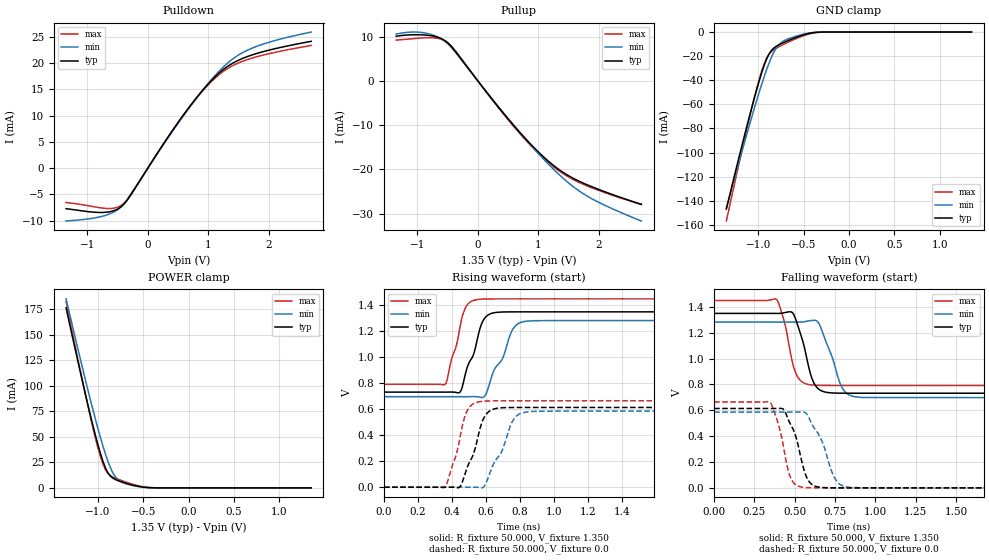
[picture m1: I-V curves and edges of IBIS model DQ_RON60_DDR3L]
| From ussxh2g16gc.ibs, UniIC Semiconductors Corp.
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|   Model DQ_RON60_DDR3L
[Model] DQ_RON60_DDR3L
Model_type I/O
Vinl =  0.540V
Vinh =  0.810V
Vmeas =  0.675V
Rref =  50.000
Vref =  0.675V
C_comp   0.966pF   0.965pF   0.967pF
[Model Spec]
Vinh   0.810V   0.776V   0.860V
Vinl   0.540V   0.506V   0.590V
Vmeas   0.675V   0.641V   0.725V
Vref   0.675V   0.641V   0.725V
Rref   50.000   NA   NA
[Temperature Range]   25.000   95.000   0.0
[Voltage Range]   1.350V   1.283V   1.450V
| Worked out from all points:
|   slope of the pulldown table from 0 to 0.203 V, typ, clamps not added: 55.8 ohm
|   slope of the pullup table from 0 to 0.203 V, typ, clamps not added: 56.9 ohm
|   GND clamp passes 1 mA (typ) near -0.43 V on its own axis
|   POWER clamp passes 1 mA (typ) near -0.52 V on its own axis
|   rising waveform, R_fixture 50.000, V_fixture 1.350: 20-80 % time 89.8ps typ, 116ps min, 75.1ps max; typ from 0.732 V to 1.35 V
|   rising waveform, R_fixture 50.000, V_fixture 0.0: 20-80 % time 92.1ps typ, 117ps min, 78.8ps max; typ from 0 V to 0.614 V
|   falling waveform, R_fixture 50.000, V_fixture 1.350: 20-80 % time 77.6ps typ, 96ps min, 68.5ps max; typ from 1.35 V to 0.732 V
|   falling waveform, R_fixture 50.000, V_fixture 0.0: 20-80 % time 87.8ps typ, 115ps min, 70.9ps max; typ from 0.614 V to 0 V
[Pulldown]
|Voltage   I(typ)   I(min)   I(max)
-1.35V    -7.722mA   -10.07mA   -6.542mA
-735mV    -8.434mA   -9.119mA   -7.633mA
-571mV    -8.147mA   -8.411mA   -7.646mA
-448mV    -7.434mA   -7.423mA   -7.166mA
-284mV    -5.144mA   -5.013mA   -5.147mA
290mV     5.156mA    5.047mA    5.173mA
659mV     11.23mA    11.12mA    11.2mA
946mV     15.38mA    15.42mA    15.23mA
1.192V    18.27mA    18.64mA    17.95mA
1.438V    20.22mA    21.1mA     19.74mA
1.725V    21.59mA    22.88mA    20.99mA
2.7V      24.18mA    25.94mA    23.39mA
[Pullup]
|Voltage   I(typ)   I(min)   I(max)
-1.35V    10.13mA    10.63mA    9.252mA
-1.072V   10.45mA    11.08mA    9.571mA
-867mV    10.39mA    10.84mA    9.791mA
-662mV    9.893mA    9.947mA    9.642mA
-498mV    8.614mA    8.428mA    8.67mA
-375mV    6.725mA    6.566mA    6.891mA
568mV     -9.667mA   -9.643mA   -9.902mA
896mV     -14.64mA   -14.85mA   -14.94mA
1.183V    -18.36mA   -19.06mA   -18.66mA
1.47V     -21.2mA    -22.74mA   -21.48mA
1.798V    -23.44mA   -25.97mA   -23.69mA
2.7V      -27.89mA   -31.66mA   -27.93mA
[GND_clamp]
|Voltage   I(typ)   I(min)   I(max)
-1.35V    -146.9mA   -146.3mA   -156.8mA
-1.154V   -87.06mA   -92.63mA   -90.37mA
-1.014V   -47.25mA   -56.31mA   -46.61mA
-958mV    -33.17mA   -42.77mA   -31.77mA
-930mV    -26.97mA   -36.36mA   -25.68mA
-902mV    -21.66mA   -30.3mA    -20.95mA
-846mV    -14.62mA   -19.69mA   -15.68mA
-790mV    -11.36mA   -12.14mA   -13.01mA
-734mV    -9.258mA   -8.096mA   -10.82mA
-566mV    -4.018mA   -3.098mA   -4.968mA
-398mV    -591.2uA   -439.3uA   -928.8uA
1.35V     0A         0A         0A
[POWER_clamp]
|Voltage   I(typ)   I(min)   I(max)
-1.35V    176.6mA    185.4mA    182.6mA
-1.226V   126.5mA    138.6mA    128.9mA
-1.114V   83.04mA    97.6mA     82.25mA
-1.03V    52.58mA    68.38mA    49.92mA
-974mV    34.42mA    50.13mA    31.33mA
-918mV    19.9mA     33.55mA    18.05mA
-890mV    14.85mA    26.22mA    14.28mA
-834mV    9.439mA    14.55mA    10.59mA
-778mV    7.089mA    7.901mA    8.471mA
-638mV    3.198mA    2.764mA    4.098mA
-414mV    126.6uA    165.9uA    198.4uA
1.35V     0A         0A         0A
[Ramp]
| variable   typ   min   max
dV/dt_r   0.369/92.016p   0.352/0.117n   0.399/78.794p
dV/dt_f   0.371/77.557p   0.351/96.063p   0.395/68.542p
R_load = 50.000
[Rising Waveform]
R_fixture= 50.000
V_fixture= 1.350
V_fixture_min= 1.283
V_fixture_max= 1.450
|time   V(typ)   V(min)   V(max)
0s        732.3mV    697.2mV    792.1mV
363ps     732.3mV    697.2mV    797.5mV
448ps     734.1mV    697.2mV    1.242V
485ps     905.3mV    697.2mV    1.396V
546ps     1.124V     696.8mV    1.444V
592ps     1.302V     702mV      1.449V
620ps     1.332V     797.4mV    1.45V
756ps     1.35V      1.215V     1.45V
834ps     1.35V      1.278V     1.45V
3ns       1.35V      1.283V     1.45V
[Rising Waveform]
R_fixture= 50.000
V_fixture= 0.0
V_fixture_min= 0.0
V_fixture_max= 0.0
|time   V(typ)   V(min)   V(max)
0s        169.2nV    1.221uV    191.4nV
355ps     -42uV      2.996uV    -2.291mV
449ps     8.193mV    -13.83uV   399.3mV
494ps     169.3mV    45.61uV    600.6mV
564ps     450.7mV    -3.339mV   659.1mV
630ps     594.1mV    136.9mV    664.6mV
691ps     611.6mV    273mV      665.2mV
751ps     613.9mV    498mV      665.3mV
811ps     614.2mV    573mV      665.3mV
3ns       614.2mV    586.3mV    665.3mV
[Falling Waveform]
R_fixture= 50.000
V_fixture= 1.350
V_fixture_min= 1.283
V_fixture_max= 1.450
|time   V(typ)   V(min)   V(max)
0s        1.35V      1.283V     1.45V
386ps     1.35V      1.283V     1.46V
440ps     1.357V     1.283V     1.265V
495ps     1.339V     1.283V     929.1mV
532ps     1.207V     1.283V     835.1mV
589ps     922.7mV    1.293V     799mV
664ps     751.7mV    1.234V     792.7mV
796ps     732.6mV    769.9mV    792.1mV
867ps     732.3mV    705.8mV    792.1mV
3ns       732.3mV    697.2mV    792.1mV
[Falling Waveform]
R_fixture= 50.000
V_fixture= 0.0
V_fixture_min= 0.0
V_fixture_max= 0.0
|time   V(typ)   V(min)   V(max)
0s        614.2mV    586.3mV    665.3mV
350ps     614.2mV    586.3mV    657.9mV
435ps     600.8mV    586.3mV    285.4mV
475ps     488.8mV    586.2mV    76.16mV
544ps     203.1mV    587.3mV    5.817mV
613ps     20.85mV    478.4mV    420.6uV
674ps     2.358mV    346.2mV    40.05uV
741ps     209.2uV    90.6mV     3.221uV
818ps     12.47uV    7.593mV    414.4nV
3ns       174.2nV    1.214uV    240.6nV
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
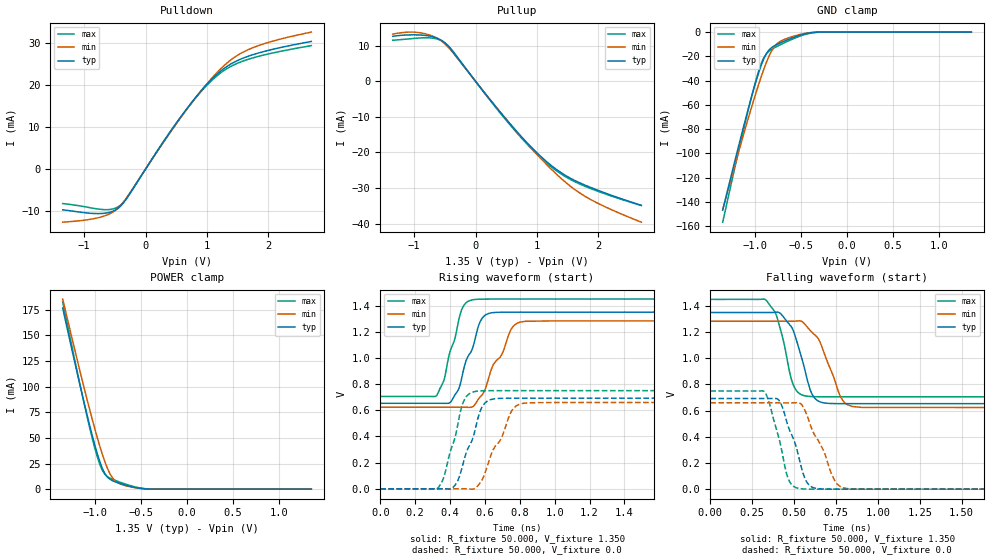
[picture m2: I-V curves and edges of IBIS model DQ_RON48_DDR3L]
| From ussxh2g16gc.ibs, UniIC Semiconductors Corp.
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|   Model DQ_RON48_DDR3L
[Model] DQ_RON48_DDR3L
Model_type I/O
Vinl =  0.540V
Vinh =  0.810V
Vmeas =  0.675V
Rref =  50.000
Vref =  0.675V
C_comp   0.966pF   0.965pF   0.967pF
[Model Spec]
Vinh   0.810V   0.776V   0.860V
Vinl   0.540V   0.506V   0.590V
Vmeas   0.675V   0.641V   0.725V
Vref   0.675V   0.641V   0.725V
Rref   50.000   NA   NA
[Temperature Range]   25.000   95.000   0.0
[Voltage Range]   1.350V   1.283V   1.450V
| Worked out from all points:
|   slope of the pulldown table from 0 to 0.203 V, typ, clamps not added: 44.6 ohm
|   slope of the pullup table from 0 to 0.203 V, typ, clamps not added: 45.5 ohm
|   GND clamp passes 1 mA (typ) near -0.43 V on its own axis
|   POWER clamp passes 1 mA (typ) near -0.52 V on its own axis
|   rising waveform, R_fixture 50.000, V_fixture 1.350: 20-80 % time 98.4ps typ, 130ps min, 81.8ps max; typ from 0.653 V to 1.35 V
|   rising waveform, R_fixture 50.000, V_fixture 0.0: 20-80 % time 99.3ps typ, 128ps min, 84.8ps max; typ from 0 V to 0.693 V
|   falling waveform, R_fixture 50.000, V_fixture 1.350: 20-80 % time 92.9ps typ, 118ps min, 79.8ps max; typ from 1.35 V to 0.653 V
|   falling waveform, R_fixture 50.000, V_fixture 0.0: 20-80 % time 102ps typ, 132ps min, 84.7ps max; typ from 0.693 V to 0 V
[Pulldown]
|Voltage   I(typ)   I(min)   I(max)
-1.35V    -9.661mA   -12.6mA    -8.186mA
-735mV    -10.55mA   -11.4mA    -9.549mA
-571mV    -10.19mA   -10.52mA   -9.563mA
-448mV    -9.296mA   -9.283mA   -8.961mA
-284mV    -6.433mA   -6.269mA   -6.436mA
290mV     6.447mA    6.311mA    6.469mA
659mV     14.05mA    13.9mA     14mA
946mV     19.24mA    19.29mA    19.05mA
1.192V    22.85mA    23.31mA    22.46mA
1.438V    25.3mA     26.4mA     24.7mA
1.725V    27.01mA    28.63mA    26.26mA
2.7V      30.25mA    32.47mA    29.27mA
[Pullup]
|Voltage   I(typ)   I(min)   I(max)
-1.35V    12.67mA    13.29mA    11.57mA
-1.072V   13.07mA    13.86mA    11.97mA
-867mV    13mA       13.56mA    12.24mA
-662mV    12.37mA    12.44mA    12.05mA
-498mV    10.77mA    10.54mA    10.84mA
-375mV    8.408mA    8.211mA    8.615mA
568mV     -12.09mA   -12.06mA   -12.38mA
896mV     -18.3mA    -18.57mA   -18.67mA
1.183V    -22.95mA   -23.83mA   -23.33mA
1.47V     -26.5mA    -28.44mA   -26.85mA
1.798V    -29.29mA   -32.48mA   -29.61mA
2.7V      -34.86mA   -39.6mA    -34.91mA
[GND_clamp]
|Voltage   I(typ)   I(min)   I(max)
-1.35V    -146.9mA   -146.3mA   -156.8mA
-1.154V   -87.06mA   -92.63mA   -90.37mA
-1.014V   -47.25mA   -56.31mA   -46.61mA
-958mV    -33.17mA   -42.77mA   -31.77mA
-930mV    -26.97mA   -36.36mA   -25.68mA
-902mV    -21.66mA   -30.3mA    -20.95mA
-846mV    -14.62mA   -19.69mA   -15.68mA
-790mV    -11.36mA   -12.14mA   -13.01mA
-734mV    -9.258mA   -8.096mA   -10.82mA
-566mV    -4.018mA   -3.098mA   -4.968mA
-398mV    -591.2uA   -439.3uA   -928.8uA
1.35V     0A         0A         0A
[POWER_clamp]
|Voltage   I(typ)   I(min)   I(max)
-1.35V    176.6mA    185.4mA    182.6mA
-1.226V   126.5mA    138.6mA    128.9mA
-1.114V   83.04mA    97.6mA     82.25mA
-1.03V    52.58mA    68.38mA    49.92mA
-974mV    34.42mA    50.13mA    31.33mA
-918mV    19.9mA     33.55mA    18.05mA
-890mV    14.85mA    26.22mA    14.28mA
-834mV    9.439mA    14.55mA    10.59mA
-778mV    7.089mA    7.901mA    8.471mA
-638mV    3.198mA    2.764mA    4.098mA
-414mV    126.6uA    165.9uA    198.4uA
1.35V     0A         0A         0A
[Ramp]
| variable   typ   min   max
dV/dt_r   0.416/99.045p   0.396/0.128n   0.450/84.592p
dV/dt_f   0.418/92.332p   0.396/0.118n   0.447/79.829p
R_load = 50.000
[Rising Waveform]
R_fixture= 50.000
V_fixture= 1.350
V_fixture_min= 1.283
V_fixture_max= 1.450
|time   V(typ)   V(min)   V(max)
0s        653.2mV    623.3mV    705.7mV
324ps     653.2mV    623.3mV    715mV
364ps     653mV      623.3mV    825.5mV
408ps     671.1mV    623.3mV    1.079V
474ps     889.9mV    623.3mV    1.39V
533ps     1.09V      630mV      1.445V
598ps     1.323V     749.6mV    1.45V
751ps     1.35V      1.221V     1.45V
801ps     1.35V      1.274V     1.45V
3ns       1.35V      1.283V     1.45V
[Rising Waveform]
R_fixture= 50.000
V_fixture= 0.0
V_fixture_min= 0.0
V_fixture_max= 0.0
|time   V(typ)   V(min)   V(max)
0s        157.3nV    1.097uV    182.3nV
332ps     8.979uV    4.384uV    7.453mV
365ps     90.37uV    3.574uV    91.58mV
440ps     50.59mV    18.29uV    459.3mV
485ps     241.9mV    160.2uV    687.4mV
549ps     479.5mV    8.874mV    744.8mV
611ps     667.7mV    162.1mV    749.8mV
754ps     692.5mV    596.5mV    750.3mV
816ps     692.6mV    652.5mV    750.3mV
3ns       692.6mV    659.5mV    750.3mV
[Falling Waveform]
R_fixture= 50.000
V_fixture= 1.350
V_fixture_min= 1.283
V_fixture_max= 1.450
|time   V(typ)   V(min)   V(max)
0s        1.35V      1.283V     1.45V
333ps     1.35V      1.283V     1.444V
400ps     1.353V     1.283V     1.306V
484ps     1.24V      1.283V     839.5mV
563ps     919.9mV    1.263V     713.7mV
597ps     756.1mV    1.212V     708.1mV
641ps     675.8mV    1.157V     706.2mV
778ps     653.3mV    704.1mV    705.7mV
847ps     653.2mV    631.6mV    705.7mV
3ns       653.2mV    623.3mV    705.7mV
[Falling Waveform]
R_fixture= 50.000
V_fixture= 0.0
V_fixture_min= 0.0
V_fixture_max= 0.0
|time   V(typ)   V(min)   V(max)
0s        692.6mV    659.5mV    750.3mV
321ps     692.5mV    659.5mV    747.7mV
413ps     673.3mV    659.5mV    372.6mV
463ps     486.6mV    659.4mV    86.98mV
528ps     247.4mV    659.5mV    5.817mV
563ps     87.33mV    607mV      1.318mV
601ps     20.4mV     476.8mV    260.2uV
745ps     64.03uV    58.83mV    752.8nV
812ps     4.268uV    5.401mV    289.2nV
3ns       139.7nV    1.088uV    228.8nV
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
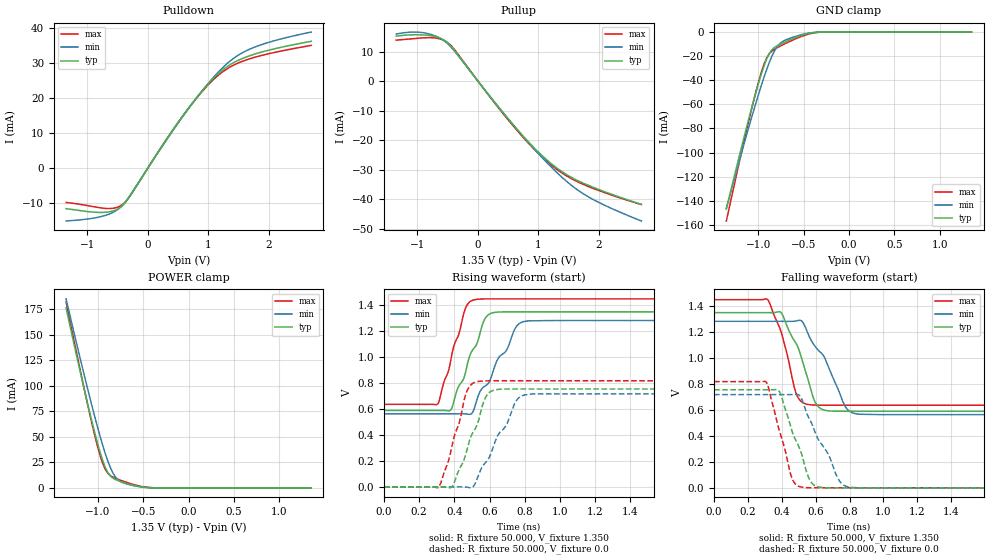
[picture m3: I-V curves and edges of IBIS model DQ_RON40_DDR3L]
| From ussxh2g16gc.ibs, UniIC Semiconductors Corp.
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|   Model DQ_RON40_DDR3L
[Model] DQ_RON40_DDR3L
Model_type I/O
Vinl =  0.540V
Vinh =  0.810V
Vmeas =  0.675V
Rref =  50.000
Vref =  0.675V
C_comp   0.966pF   0.965pF   0.967pF
[Model Spec]
Vinh   0.810V   0.776V   0.860V
Vinl   0.540V   0.506V   0.590V
Vmeas   0.675V   0.641V   0.725V
Vref   0.675V   0.641V   0.725V
Rref   50.000   NA   NA
[Temperature Range]   25.000   95.000   0.0
[Voltage Range]   1.350V   1.283V   1.450V
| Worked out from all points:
|   slope of the pulldown table from 0 to 0.203 V, typ, clamps not added: 37.2 ohm
|   slope of the pullup table from 0 to 0.203 V, typ, clamps not added: 38 ohm
|   GND clamp passes 1 mA (typ) near -0.43 V on its own axis
|   POWER clamp passes 1 mA (typ) near -0.52 V on its own axis
|   rising waveform, R_fixture 50.000, V_fixture 1.350: 20-80 % time 134ps typ, 184ps min, 106ps max; typ from 0.59 V to 1.35 V
|   rising waveform, R_fixture 50.000, V_fixture 0.0: 20-80 % time 122ps typ, 170ps min, 96.3ps max; typ from 0 V to 0.756 V
|   falling waveform, R_fixture 50.000, V_fixture 1.350: 20-80 % time 128ps typ, 175ps min, 101ps max; typ from 1.35 V to 0.59 V
|   falling waveform, R_fixture 50.000, V_fixture 0.0: 20-80 % time 119ps typ, 161ps min, 97.6ps max; typ from 0.756 V to 0 V
[Pulldown]
|Voltage   I(typ)   I(min)   I(max)
-1.35V    -11.58mA   -15.1mA    -9.807mA
-735mV    -12.64mA   -13.67mA   -11.44mA
-571mV    -12.21mA   -12.61mA   -11.46mA
-448mV    -11.14mA   -11.13mA   -10.74mA
-284mV    -7.708mA   -7.512mA   -7.711mA
290mV     7.725mA    7.562mA    7.75mA
659mV     16.83mA    16.66mA    16.78mA
946mV     23.05mA    23.11mA    22.82mA
1.192V    27.38mA    27.92mA    26.9mA
1.438V    30.3mA     31.62mA    29.59mA
1.725V    32.35mA    34.28mA    31.45mA
2.7V      36.23mA    38.87mA    35.06mA
[Pullup]
|Voltage   I(typ)   I(min)   I(max)
-1.35V    15.19mA    15.93mA    13.87mA
-1.072V   15.67mA    16.61mA    14.35mA
-867mV    15.58mA    16.25mA    14.68mA
-662mV    14.83mA    14.91mA    14.45mA
-498mV    12.91mA    12.63mA    12.99mA
-375mV    10.07mA    9.838mA    10.32mA
568mV     -14.48mA   -14.45mA   -14.83mA
896mV     -21.93mA   -22.25mA   -22.38mA
1.183V    -27.5mA    -28.54mA   -27.96mA
1.47V     -31.76mA   -34.06mA   -32.18mA
1.798V    -35.1mA    -38.89mA   -35.48mA
2.7V      -41.76mA   -47.4mA    -41.83mA
[GND_clamp]
|Voltage   I(typ)   I(min)   I(max)
-1.35V    -146.9mA   -146.3mA   -156.8mA
-1.154V   -87.06mA   -92.63mA   -90.37mA
-1.014V   -47.25mA   -56.31mA   -46.61mA
-958mV    -33.17mA   -42.77mA   -31.77mA
-930mV    -26.97mA   -36.36mA   -25.68mA
-902mV    -21.66mA   -30.3mA    -20.95mA
-846mV    -14.62mA   -19.69mA   -15.68mA
-790mV    -11.36mA   -12.14mA   -13.01mA
-734mV    -9.258mA   -8.096mA   -10.82mA
-566mV    -4.018mA   -3.098mA   -4.968mA
-398mV    -591.2uA   -439.3uA   -928.8uA
1.35V     0A         0A         0A
[POWER_clamp]
|Voltage   I(typ)   I(min)   I(max)
-1.35V    176.6mA    185.4mA    182.6mA
-1.226V   126.5mA    138.6mA    128.9mA
-1.114V   83.04mA    97.6mA     82.25mA
-1.03V    52.58mA    68.38mA    49.92mA
-974mV    34.42mA    50.13mA    31.33mA
-918mV    19.9mA     33.55mA    18.05mA
-890mV    14.85mA    26.22mA    14.28mA
-834mV    9.439mA    14.55mA    10.59mA
-778mV    7.089mA    7.901mA    8.471mA
-638mV    3.198mA    2.764mA    4.098mA
-414mV    126.6uA    165.9uA    198.4uA
1.35V     0A         0A         0A
[Ramp]
| variable   typ   min   max
dV/dt_r   0.453/0.121n   0.431/0.169n   0.491/96.165p
dV/dt_f   0.456/0.128n   0.431/0.176n   0.488/0.100n
R_load = 50.000
[Rising Waveform]
R_fixture= 50.000
V_fixture= 1.350
V_fixture_min= 1.283
V_fixture_max= 1.450
|time   V(typ)   V(min)   V(max)
0s        589.8mV    563.9mV    636.7mV
307ps     589.8mV    563.9mV    641.3mV
382ps     598.9mV    563.8mV    994.6mV
464ps     886.5mV    563.1mV    1.38V
497ps     1.041V     564.3mV    1.435V
522ps     1.088V     644.1mV    1.445V
592ps     1.326V     796.5mV    1.45V
745ps     1.35V      1.221V     1.45V
797ps     1.35V      1.276V     1.45V
3ns       1.35V      1.283V     1.45V
[Rising Waveform]
R_fixture= 50.000
V_fixture= 0.0
V_fixture_min= 0.0
V_fixture_max= 0.0
|time   V(typ)   V(min)   V(max)
0s        148nV      998nV      175.6nV
314ps     21.36uV    2.887uV    4.402mV
390ps     7.276mV    -48.9uV    337mV
469ps     271.7mV    -1.084mV   731.2mV
535ps     501.8mV    82.53mV    812.9mV
570ps     670.1mV    177.3mV    817.2mV
603ps     732.5mV    242.9mV    818.1mV
752ps     755.6mV    665.2mV    818.5mV
795ps     755.6mV    708.3mV    818.5mV
3ns       755.6mV    718.3mV    818.5mV
[Falling Waveform]
R_fixture= 50.000
V_fixture= 1.350
V_fixture_min= 1.283
V_fixture_max= 1.450
|time   V(typ)   V(min)   V(max)
0s        1.35V      1.283V     1.45V
315ps     1.35V      1.283V     1.452V
401ps     1.341V     1.283V     1.178V
481ps     1.119V     1.285V     741.1mV
519ps     989.3mV    1.284V     660.6mV
552ps     846.7mV    1.196V     643mV
625ps     614mV      1.048V     637mV
773ps     589.9mV    628.9mV    636.7mV
835ps     589.8mV    571mV      636.7mV
3ns       589.8mV    563.9mV    636.7mV
[Falling Waveform]
R_fixture= 50.000
V_fixture= 0.0
V_fixture_min= 0.0
V_fixture_max= 0.0
|time   V(typ)   V(min)   V(max)
0s        755.6mV    718.3mV    818.5mV
305ps     755.5mV    718.3mV    818mV
387ps     739.4mV    718.3mV    434mV
462ps     429.8mV    718.4mV    67.54mV
512ps     279.2mV    698.9mV    6.791mV
551ps     103.6mV    562.4mV    1.097mV
588ps     23.25mV    457.8mV    194.8uV
741ps     30.01uV    50.75mV    406.8nV
787ps     4.187uV    8.759mV    248.8nV
3ns       95.89nV    981nV      156.4nV
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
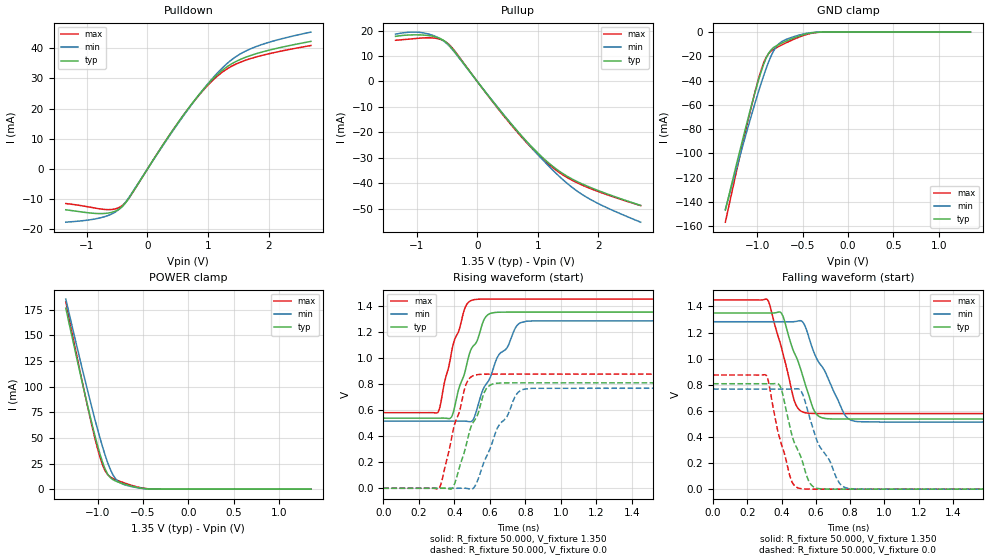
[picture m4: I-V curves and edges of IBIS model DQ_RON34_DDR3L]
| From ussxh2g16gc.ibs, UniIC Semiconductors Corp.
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|   Model DQ_RON34_DDR3L
[Model] DQ_RON34_DDR3L
Model_type I/O
Vinl =  0.540V
Vinh =  0.810V
Vmeas =  0.675V
Rref =  50.000
Vref =  0.675V
C_comp   0.966pF   0.965pF   0.967pF
[Model Spec]
Vinh   0.810V   0.776V   0.860V
Vinl   0.540V   0.506V   0.590V
Vmeas   0.675V   0.641V   0.725V
Vref   0.675V   0.641V   0.725V
Rref   50.000   NA   NA
[Temperature Range]   25.000   95.000   0.0
[Voltage Range]   1.350V   1.283V   1.450V
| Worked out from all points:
|   slope of the pulldown table from 0 to 0.203 V, typ, clamps not added: 31.9 ohm
|   slope of the pullup table from 0 to 0.203 V, typ, clamps not added: 32.6 ohm
|   GND clamp passes 1 mA (typ) near -0.43 V on its own axis
|   POWER clamp passes 1 mA (typ) near -0.52 V on its own axis
|   rising waveform, R_fixture 50.000, V_fixture 1.350: 20-80 % time 128ps typ, 174ps min, 102ps max; typ from 0.537 V to 1.35 V
|   rising waveform, R_fixture 50.000, V_fixture 0.0: 20-80 % time 120ps typ, 161ps min, 97.7ps max; typ from 0 V to 0.808 V
|   falling waveform, R_fixture 50.000, V_fixture 1.350: 20-80 % time 125ps typ, 167ps min, 103ps max; typ from 1.35 V to 0.537 V
|   falling waveform, R_fixture 50.000, V_fixture 0.0: 20-80 % time 113ps typ, 150ps min, 94ps max; typ from 0.808 V to 0 V
[Pulldown]
|Voltage   I(typ)   I(min)   I(max)
-1.35V    -13.51mA   -17.62mA   -11.45mA
-735mV    -14.75mA   -15.95mA   -13.35mA
-571mV    -14.25mA   -14.71mA   -13.37mA
-448mV    -12.99mA   -12.97mA   -12.53mA
-284mV    -8.986mA   -8.758mA   -8.991mA
290mV     9.006mA    8.816mA    9.037mA
659mV     19.63mA    19.42mA    19.56mA
946mV     26.88mA    26.94mA    26.61mA
1.192V    31.92mA    32.56mA    31.37mA
1.438V    35.34mA    36.87mA    34.5mA
1.725V    37.72mA    39.98mA    36.68mA
2.7V      42.25mA    45.33mA    40.89mA
[Pullup]
|Voltage   I(typ)   I(min)   I(max)
-1.35V    17.72mA    18.59mA    16.18mA
-1.072V   18.28mA    19.38mA    16.74mA
-867mV    18.18mA    18.96mA    17.12mA
-662mV    17.3mA     17.39mA    16.86mA
-498mV    15.05mA    14.73mA    15.15mA
-375mV    11.75mA    11.47mA    12.04mA
568mV     -16.88mA   -16.85mA   -17.3mA
896mV     -25.56mA   -25.94mA   -26.09mA
1.183V    -32.06mA   -33.29mA   -32.6mA
1.47V     -37.02mA   -39.71mA   -37.52mA
1.798V    -40.91mA   -45.34mA   -41.37mA
2.7V      -48.67mA   -55.27mA   -48.76mA
[GND_clamp]
|Voltage   I(typ)   I(min)   I(max)
-1.35V    -146.9mA   -146.3mA   -156.8mA
-1.154V   -87.06mA   -92.63mA   -90.37mA
-1.014V   -47.25mA   -56.31mA   -46.61mA
-958mV    -33.17mA   -42.77mA   -31.77mA
-930mV    -26.97mA   -36.36mA   -25.68mA
-902mV    -21.66mA   -30.3mA    -20.95mA
-846mV    -14.62mA   -19.69mA   -15.68mA
-790mV    -11.36mA   -12.14mA   -13.01mA
-734mV    -9.258mA   -8.096mA   -10.82mA
-566mV    -4.018mA   -3.098mA   -4.968mA
-398mV    -591.2uA   -439.3uA   -928.8uA
1.35V     0A         0A         0A
[POWER_clamp]
|Voltage   I(typ)   I(min)   I(max)
-1.35V    176.6mA    185.4mA    182.6mA
-1.226V   126.5mA    138.6mA    128.9mA
-1.114V   83.04mA    97.6mA     82.25mA
-1.03V    52.58mA    68.38mA    49.92mA
-974mV    34.42mA    50.13mA    31.33mA
-918mV    19.9mA     33.55mA    18.05mA
-890mV    14.85mA    26.22mA    14.28mA
-834mV    9.439mA    14.55mA    10.59mA
-778mV    7.089mA    7.901mA    8.471mA
-638mV    3.198mA    2.764mA    4.098mA
-414mV    126.6uA    165.9uA    198.4uA
1.35V     0A         0A         0A
[Ramp]
| variable   typ   min   max
dV/dt_r   0.485/0.120n   0.460/0.161n   0.525/97.835p
dV/dt_f   0.488/0.125n   0.461/0.167n   0.522/0.103n
R_load = 50.000
[Rising Waveform]
R_fixture= 50.000
V_fixture= 1.350
V_fixture_min= 1.283
V_fixture_max= 1.450
|time   V(typ)   V(min)   V(max)
0s        537.3mV    514.5mV    579.5mV
307ps     537.3mV    514.5mV    580.4mV
384ps     545.9mV    514.5mV    1.043V
459ps     887.4mV    514.5mV    1.379V
507ps     1.091V     528mV      1.444V
593ps     1.334V     824.6mV    1.45V
639ps     1.348V     995.1mV    1.45V
745ps     1.35V      1.232V     1.45V
806ps     1.35V      1.28V      1.45V
3ns       1.35V      1.283V     1.45V
[Rising Waveform]
R_fixture= 50.000
V_fixture= 0.0
V_fixture_min= 0.0
V_fixture_max= 0.0
|time   V(typ)   V(min)   V(max)
0s        140.3nV    915.5nV    169.7nV
313ps     -21.49uV   3.362uV    -927.8uV
395ps     15.21mV    -61.63uV   456.5mV
467ps     333mV      -390.9uV   800.3mV
516ps     524.4mV    16.05mV    867mV
569ps     735.9mV    207.5mV    874.2mV
600ps     789.3mV    299.8mV    874.7mV
641ps     804.9mV    459.5mV    874.9mV
789ps     807.9mV    758.4mV    874.9mV
3ns       807.9mV    767.3mV    874.9mV
[Falling Waveform]
R_fixture= 50.000
V_fixture= 1.350
V_fixture_min= 1.283
V_fixture_max= 1.450
|time   V(typ)   V(min)   V(max)
0s        1.35V      1.283V     1.45V
316ps     1.35V      1.283V     1.453V
400ps     1.347V     1.283V     1.079V
476ps     1.039V     1.284V     670.6mV
535ps     816mV      1.255V     586.6mV
584ps     618.5mV    1.064V     580.3mV
613ps     562.1mV    980.2mV    579.7mV
764ps     537.4mV    579.1mV    579.5mV
827ps     537.3mV    520.4mV    579.5mV
3ns       537.3mV    514.5mV    579.5mV
[Falling Waveform]
R_fixture= 50.000
V_fixture= 0.0
V_fixture_min= 0.0
V_fixture_max= 0.0
|time   V(typ)   V(min)   V(max)
0s        807.9mV    767.3mV    874.9mV
311ps     807.8mV    767.3mV    871.1mV
395ps     777.9mV    767.3mV    361.5mV
456ps     435.6mV    767.1mV    69.66mV
505ps     269.7mV    764.4mV    6.098mV
555ps     71.88mV    587.9mV    490.7uV
584ps     19.73mV    462.8mV    115.2uV
722ps     36.48uV    81.4mV     400nV
783ps     2.599uV    7.159mV    255.7nV
3ns       78.32nV    867.5nV    176.3nV
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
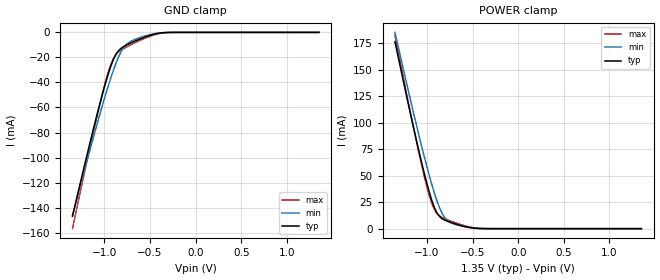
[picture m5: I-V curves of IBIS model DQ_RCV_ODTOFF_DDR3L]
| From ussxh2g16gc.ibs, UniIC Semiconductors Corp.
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|   Model DQ_RCV_ODTOFF_DDR3L
[Model] DQ_RCV_ODTOFF_DDR3L
Model_type Input
Vinl =  0.540V
Vinh =  0.810V
C_comp   0.966pF   0.965pF   0.967pF
[Model Spec]
Vinh   0.810V   0.776V   0.860V
Vinl   0.540V   0.506V   0.590V
[Temperature Range]   25.000   95.000   0.0
[Voltage Range]   1.350V   1.283V   1.450V
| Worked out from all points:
|   GND clamp passes 1 mA (typ) near -0.43 V on its own axis
|   POWER clamp passes 1 mA (typ) near -0.52 V on its own axis
[GND_clamp]
|Voltage   I(typ)   I(min)   I(max)
-1.35V    -146.9mA   -146.3mA   -156.8mA
-1.154V   -87.06mA   -92.63mA   -90.37mA
-1.014V   -47.25mA   -56.31mA   -46.61mA
-958mV    -33.17mA   -42.77mA   -31.77mA
-930mV    -26.97mA   -36.36mA   -25.68mA
-902mV    -21.66mA   -30.3mA    -20.95mA
-846mV    -14.62mA   -19.69mA   -15.68mA
-790mV    -11.36mA   -12.14mA   -13.01mA
-734mV    -9.258mA   -8.096mA   -10.82mA
-566mV    -4.018mA   -3.098mA   -4.968mA
-398mV    -591.2uA   -439.3uA   -928.8uA
1.35V     0A         0A         0A
[POWER_clamp]
|Voltage   I(typ)   I(min)   I(max)
-1.35V    176.6mA    185.4mA    182.6mA
-1.226V   126.5mA    138.6mA    128.9mA
-1.114V   83.04mA    97.6mA     82.25mA
-1.03V    52.58mA    68.38mA    49.92mA
-974mV    34.42mA    50.13mA    31.33mA
-918mV    19.9mA     33.55mA    18.05mA
-890mV    14.85mA    26.22mA    14.28mA
-834mV    9.439mA    14.55mA    10.59mA
-778mV    7.089mA    7.901mA    8.471mA
-638mV    3.198mA    2.764mA    4.098mA
-414mV    126.6uA    165.9uA    198.4uA
1.35V     0A         0A         0A
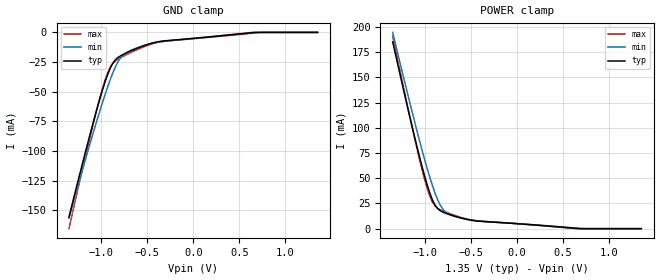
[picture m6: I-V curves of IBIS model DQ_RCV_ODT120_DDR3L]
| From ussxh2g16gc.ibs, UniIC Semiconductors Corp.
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|   Model DQ_RCV_ODT120_DDR3L
[Model] DQ_RCV_ODT120_DDR3L
Model_type Input
Vinl =  0.540V
Vinh =  0.810V
C_comp   0.966pF   0.965pF   0.967pF
[Model Spec]
Vinh   0.810V   0.776V   0.860V
Vinl   0.540V   0.506V   0.590V
[Temperature Range]   25.000   95.000   0.0
[Voltage Range]   1.350V   1.283V   1.450V
[GND_clamp]
|Voltage   I(typ)   I(min)   I(max)
-1.35V    -155.9mA   -156.8mA   -165.6mA
-1.154V   -95.85mA   -102.7mA   -98.99mA
-1.014V   -55.93mA   -66.14mA   -55.14mA
-930mV    -35.58mA   -46.03mA   -34.17mA
-902mV    -30.24mA   -39.91mA   -29.42mA
-846mV    -23.14mA   -29.18mA   -24.11mA
-790mV    -19.82mA   -21.51mA   -21.41mA
-734mV    -17.64mA   -17.32mA   -19.17mA
-594mV    -12.95mA   -12.57mA   -14.05mA
-398mV    -8.128mA   -8.424mA   -8.63mA
638mV     -251.5uA   -28.29uA   -706.4uA
1.35V     0A         0A         0A
[POWER_clamp]
|Voltage   I(typ)   I(min)   I(max)
-1.35V    185.2mA    194.6mA    190.9mA
-1.114V   91.62mA    106.7mA    90.46mA
-1.03V    61.11mA    77.45mA    58.1mA
-974mV    42.92mA    59.15mA    39.5mA
-918mV    28.35mA    42.51mA    26.21mA
-890mV    23.28mA    35.15mA    22.43mA
-834mV    17.82mA    23.39mA    18.72mA
-778mV    15.41mA    16.65mA    16.56mA
-638mV    11.3mA     11.2mA     12.04mA
-386mV    7.244mA    7.486mA    7.248mA
650mV     229.5uA    0A         519.8uA
1.35V     0A         0A         0A
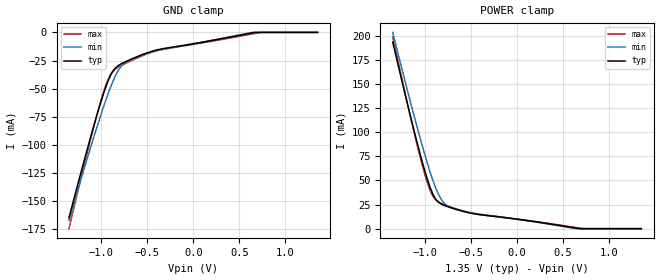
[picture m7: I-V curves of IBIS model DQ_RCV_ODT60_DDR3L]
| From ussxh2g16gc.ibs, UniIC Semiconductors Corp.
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|   Model DQ_RCV_ODT60_DDR3L
[Model] DQ_RCV_ODT60_DDR3L
Model_type Input
Vinl =  0.540V
Vinh =  0.810V
C_comp   0.966pF   0.965pF   0.967pF
[Model Spec]
Vinh   0.810V   0.776V   0.860V
Vinl   0.540V   0.506V   0.590V
[Temperature Range]   25.000   95.000   0.0
[Voltage Range]   1.350V   1.283V   1.450V
[GND_clamp]
|Voltage   I(typ)   I(min)   I(max)
-1.35V    -164.8mA   -167.1mA   -174.3mA
-1.154V   -104.6mA   -112.7mA   -107.6mA
-1.014V   -64.57mA   -75.87mA   -63.63mA
-930mV    -44.15mA   -55.6mA    -42.61mA
-902mV    -38.78mA   -49.43mA   -37.85mA
-846mV    -31.62mA   -38.58mA   -32.51mA
-790mV    -28.24mA   -30.79mA   -29.77mA
-734mV    -25.99mA   -26.47mA   -27.48mA
-370mV    -15.11mA   -15.83mA   -15.71mA
638mV     -505uA     -51.4uA    -1.415mA
750mV     0A         0A         0A
1.35V     0A         0A         0A
[POWER_clamp]
|Voltage   I(typ)   I(min)   I(max)
-1.35V    193.8mA    203.7mA    199.1mA
-1.114V   100.1mA    115.8mA    98.59mA
-1.03V    69.57mA    86.43mA    66.22mA
-974mV    51.35mA    68.08mA    47.61mA
-918mV    36.74mA    51.37mA    34.3mA
-890mV    31.65mA    43.97mA    30.51mA
-834mV    26.13mA    32.14mA    26.77mA
-778mV    23.66mA    25.3mA     24.58mA
-666mV    20.13mA    20.3mA     20.8mA
-442mV    15.1mA     15.57mA    15.13mA
622mV     886.5uA    316.9uA    1.45mA
1.35V     0A         0A         0A
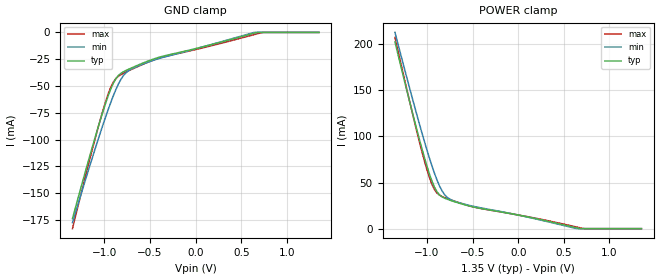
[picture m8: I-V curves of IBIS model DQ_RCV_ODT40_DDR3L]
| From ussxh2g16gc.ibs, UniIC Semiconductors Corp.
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|   Model DQ_RCV_ODT40_DDR3L
[Model] DQ_RCV_ODT40_DDR3L
Model_type Input
Vinl =  0.540V
Vinh =  0.810V
C_comp   0.966pF   0.965pF   0.967pF
[Model Spec]
Vinh   0.810V   0.776V   0.860V
Vinl   0.540V   0.506V   0.590V
[Temperature Range]   25.000   95.000   0.0
[Voltage Range]   1.350V   1.283V   1.450V
[GND_clamp]
|Voltage   I(typ)   I(min)   I(max)
-1.35V    -173.6mA   -177.4mA   -183mA
-1.154V   -113.3mA   -122.7mA   -116.1mA
-1.014V   -73.19mA   -85.62mA   -72.12mA
-930mV    -52.69mA   -65.19mA   -51.05mA
-902mV    -47.3mA    -58.96mA   -46.27mA
-846mV    -40.08mA   -48mA      -40.89mA
-762mV    -35.42mA   -37.49mA   -36.93mA
-566mV    -28.17mA   -29.17mA   -29.32mA
-342mV    -21.84mA   -22.94mA   -22.59mA
638mV     -757.9uA   -84.43uA   -2.121mA
750mV     0A         0A         0A
1.35V     0A         0A         0A
[POWER_clamp]
|Voltage   I(typ)   I(min)   I(max)
-1.35V    202.4mA    212.8mA    207.3mA
-1.114V   108.6mA    124.8mA    106.7mA
-1.03V    78.04mA    95.43mA    74.35mA
-974mV    59.79mA    77.03mA    55.73mA
-918mV    45.14mA    60.26mA    42.4mA
-890mV    40.02mA    52.83mA    38.61mA
-834mV    34.46mA    40.91mA    34.84mA
-778mV    31.93mA    33.98mA    32.62mA
-526mV    24.31mA    24.99mA    24.48mA
650mV     678.6uA    0A         1.541mA
734mV     0A         0A         0A
1.35V     0A         0A         0A
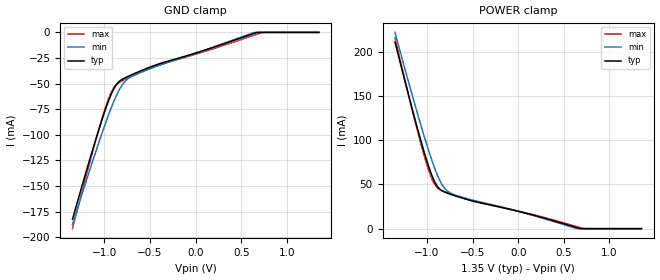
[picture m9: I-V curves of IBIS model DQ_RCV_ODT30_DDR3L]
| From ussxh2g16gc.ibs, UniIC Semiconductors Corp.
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|   Model DQ_RCV_ODT30_DDR3L
[Model] DQ_RCV_ODT30_DDR3L
Model_type Input
Vinl =  0.540V
Vinh =  0.810V
C_comp   0.966pF   0.965pF   0.967pF
[Model Spec]
Vinh   0.810V   0.776V   0.860V
Vinl   0.540V   0.506V   0.590V
[Temperature Range]   25.000   95.000   0.0
[Voltage Range]   1.350V   1.283V   1.450V
[GND_clamp]
|Voltage   I(typ)   I(min)   I(max)
-1.35V    -182.5mA   -187.7mA   -191.7mA
-1.154V   -122.1mA   -132.7mA   -124.7mA
-1.014V   -81.85mA   -95.38mA   -80.64mA
-930mV    -61.28mA   -74.79mA   -59.51mA
-902mV    -55.86mA   -68.5mA    -54.72mA
-846mV    -48.59mA   -57.42mA   -49.31mA
-762mV    -43.83mA   -46.72mA   -45.29mA
-650mV    -39.39mA   -40.96mA   -40.71mA
-370mV    -29.83mA   -31.34mA   -30.8mA
638mV     -1.014mA   -110.4uA   -2.834mA
750mV     0A         0A         0A
1.35V     0A         0A         0A
[POWER_clamp]
|Voltage   I(typ)   I(min)   I(max)
-1.35V    210.9mA    221.8mA    215.5mA
-1.114V   117.1mA    133.8mA    114.9mA
-1.03V    86.51mA    104.4mA    82.48mA
-974mV    68.22mA    85.96mA    63.84mA
-918mV    53.53mA    69.13mA    50.5mA
-890mV    48.39mA    61.66mA    46.69mA
-834mV    42.78mA    49.66mA    42.91mA
-778mV    40.18mA    42.64mA    40.65mA
-610mV    34.54mA    35.38mA    34.77mA
650mV     900.4uA    0A         2.046mA
734mV     0A         0A         0A
1.35V     0A         0A         0A
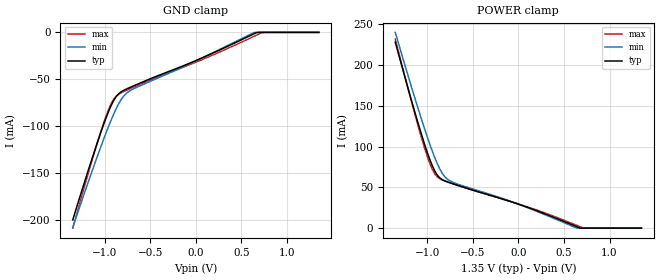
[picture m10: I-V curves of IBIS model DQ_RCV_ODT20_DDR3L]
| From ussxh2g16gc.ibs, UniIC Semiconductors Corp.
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|   Model DQ_RCV_ODT20_DDR3L
[Model] DQ_RCV_ODT20_DDR3L
Model_type Input
Vinl =  0.540V
Vinh =  0.810V
C_comp   0.966pF   0.965pF   0.967pF
[Model Spec]
Vinh   0.810V   0.776V   0.860V
Vinl   0.540V   0.506V   0.590V
[Temperature Range]   25.000   95.000   0.0
[Voltage Range]   1.350V   1.283V   1.450V
[GND_clamp]
|Voltage   I(typ)   I(min)   I(max)
-1.35V    -200.3mA   -208.3mA   -209.1mA
-1.154V   -139.5mA   -152.6mA   -141.8mA
-1.014V   -99.08mA   -114.8mA   -97.58mA
-930mV    -78.37mA   -93.92mA   -76.37mA
-874mV    -68.58mA   -81.56mA   -68.22mA
-790mV    -61.86mA   -67.91mA   -63.17mA
-706mV    -58.12mA   -61.44mA   -59.51mA
22mV      -29.21mA   -29.52mA   -31.02mA
638mV     -1.516mA   -163.3uA   -4.242mA
666mV     -220.1uA   0A         -2.975mA
750mV     0A         0A         0A
1.35V     0A         0A         0A
[POWER_clamp]
|Voltage   I(typ)   I(min)   I(max)
-1.35V    228mA      240mA      231.9mA
-1.17V    155.7mA    172.3mA    154.2mA
-1.03V    103.4mA    122.4mA    98.72mA
-946mV    77.08mA    95.1mA     72.48mA
-890mV    65.12mA    79.33mA    62.86mA
-806mV    57.89mA    62.95mA    57.81mA
-722mV    54.55mA    56.34mA    54.58mA
-22mV     30.22mA    30.34mA    30.43mA
622mV     2.644mA    937.6uA    4.322mA
678mV     57.48uA    0A         1.81mA
734mV     0A         0A         0A
1.35V     0A         0A         0A
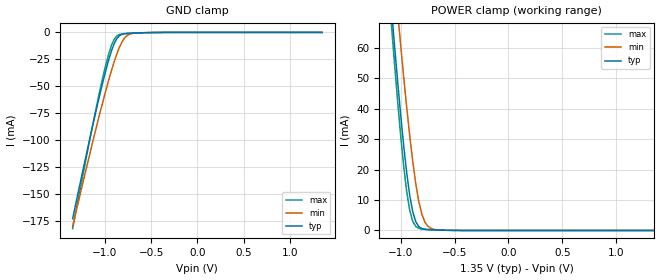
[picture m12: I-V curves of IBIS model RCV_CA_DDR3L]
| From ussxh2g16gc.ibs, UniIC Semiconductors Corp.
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|   Model RCV_CA_DDR3L
[Model] RCV_CA_DDR3L
Model_type Input
Vinl =  0.540V
Vinh =  0.810V
C_comp   0.690pF   0.690pF   0.690pF
[Model Spec]
Vinh   0.810V   0.776V   0.860V
Vinl   0.540V   0.506V   0.590V
[Temperature Range]   25.000   95.000   0.0
[Voltage Range]   1.350V   1.283V   1.450V
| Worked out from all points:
|   GND clamp passes 1 mA (typ) near -0.77 V on its own axis
|   POWER clamp passes 1 mA (typ) near -0.82 V on its own axis
[GND_clamp]
|Voltage   I(typ)   I(min)   I(max)
-1.35V    -172.8mA   -179.9mA   -182mA
-1.154V   -94.6mA    -109.1mA   -95.07mA
-1.014V   -42.97mA   -61.42mA   -38.33mA
-958mV    -25.01mA   -43.77mA   -19.55mA
-930mV    -17.28mA   -35.47mA   -12.14mA
-902mV    -10.85mA   -27.68mA   -6.739mA
-874mV    -6.141mA   -20.55mA   -3.564mA
-818mV    -1.856mA   -9.196mA   -1.478mA
-790mV    -1.231mA   -5.438mA   -1.202mA
-734mV    -789.8uA   -1.68mA    -917.2uA
-678mV    -590.6uA   -657uA     -709.5uA
1.35V     0A         0A         0A
[POWER_clamp]
|Voltage   I(typ)   I(min)   I(max)
-1.35V    193.8mA    208.2mA    196.7mA
-1.086V   72.37mA    94.37mA    67.01mA
-1.058V   60.5mA     82.99mA    54.49mA
-1.03V    49.05mA    71.85mA    42.52mA
-1.002V   38.16mA    61.01mA    31.33mA
-946mV    19.06mA    40.6mA     12.86mA
-918mV    11.61mA    31.29mA    6.694mA
-862mV    2.921mA    15.53mA    1.362mA
-834mV    1.333mA    9.671mA    710.4uA
-778mV    401.9uA    2.844mA    359uA
-694mV    183.7uA    385.9uA    218uA
1.35V     0A         0A         0A
